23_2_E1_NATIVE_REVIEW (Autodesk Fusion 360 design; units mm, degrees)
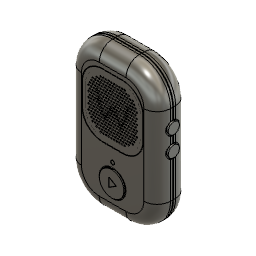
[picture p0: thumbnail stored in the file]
description: Open CASCADE Model
part number: 23_2_E1_FRONT_CONTROL_REVISION
description: Part Number
part number: 11_status_lightpipe_part
part number: 11_status_lightpipe
part number: 08_play_guide_part
part number: 08_play_guide
part number: 13_volume_down_diaphragm_part
part number: 13_volume_down_diaphragm
part number: 09_play_cap_part
part number: 09_play_cap
part number: 13_PTT_diaphragm_part
base_feature "Base Feature1"
base_feature "Base Feature1"
base_feature "Base Feature1"
base_feature "Base Feature1"
base_feature "Base Feature1"
base_feature "Base Feature1"
base_feature "Base Feature1"
base_feature "Base Feature1"
base_feature "Base Feature1"
base_feature "Base Feature1"
base_feature "Base Feature1"
base_feature "Base Feature1"
base_feature "Base Feature1"
base_feature "Base Feature1"
base_feature "Base Feature1"
base_feature "Base Feature1"
base_feature "Base Feature1"
base_feature "Base Feature1"
base_feature "Base Feature1"
base_feature "Base Feature1"
base_feature "Base Feature1"
base_feature "Base Feature1"
base_feature "Base Feature1"
base_feature "Base Feature1"
base_feature "Base Feature1"
base_feature "Base Feature1"
base_feature "Base Feature1"
base_feature "Base Feature1"
base_feature "Base Feature1"
base_feature "Base Feature1"
base_feature "Base Feature1"
base_feature "Base Feature1"
base_feature "Base Feature1"
base_feature "Base Feature1"
base_feature "Base Feature1"
base_feature "Base Feature1"
base_feature "Base Feature1"
base_feature "Base Feature1"
base_feature "Base Feature1"
base_feature "Base Feature1"
base_feature "Base Feature1"
base_feature "Base Feature1"
base_feature "Base Feature1"
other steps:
create_component "CreateComponent1"
create_component "CreateComponent1"
create_component "CreateComponent1"
create_component "CreateComponent2"
create_component "CreateComponent1"
create_component "CreateComponent3"
create_component "CreateComponent1"
create_component "CreateComponent4"
create_component "CreateComponent1"
create_component "CreateComponent5"
create_component "CreateComponent1"
create_component "CreateComponent6"
create_component "CreateComponent1"
create_component "CreateComponent7"
create_component "CreateComponent1"
create_component "CreateComponent8"
create_component "CreateComponent1"
create_component "CreateComponent9"
create_component "CreateComponent1"
create_component "CreateComponent10"
create_component "CreateComponent1"
create_component "CreateComponent11"
create_component "CreateComponent1"
create_component "CreateComponent12"
create_component "CreateComponent1"
create_component "CreateComponent13"
create_component "CreateComponent1"
create_component "CreateComponent14"
create_component "CreateComponent1"
create_component "CreateComponent15"
create_component "CreateComponent1"
create_component "CreateComponent16"
create_component "CreateComponent1"
create_component "CreateComponent17"
create_component "CreateComponent1"
create_component "CreateComponent18"
create_component "CreateComponent1"
create_component "CreateComponent19"
create_component "CreateComponent1"
create_component "CreateComponent20"
create_component "CreateComponent1"
create_component "CreateComponent21"
create_component "CreateComponent1"
create_component "CreateComponent22"
create_component "CreateComponent1"
create_component "CreateComponent23"
create_component "CreateComponent1"
create_component "CreateComponent24"
create_component "CreateComponent1"
create_component "CreateComponent25"
create_component "CreateComponent1"
create_component "CreateComponent26"
create_component "CreateComponent1"
create_component "CreateComponent27"
create_component "CreateComponent1"
create_component "CreateComponent28"
create_component "CreateComponent1"
create_component "CreateComponent29"
create_component "CreateComponent1"
create_component "CreateComponent30"
create_component "CreateComponent1"
create_component "CreateComponent31"
create_component "CreateComponent1"
create_component "CreateComponent32"
create_component "CreateComponent1"
create_component "CreateComponent33"
create_component "CreateComponent1"
create_component "CreateComponent34"
create_component "CreateComponent1"
create_component "CreateComponent35"
create_component "CreateComponent1"
create_component "CreateComponent36"
create_component "CreateComponent1"
create_component "CreateComponent37"
create_component "CreateComponent1"
create_component "CreateComponent38"
create_component "CreateComponent1"
create_component "CreateComponent39"
create_component "CreateComponent1"
create_component "CreateComponent40"
create_component "CreateComponent1"
create_component "CreateComponent41"
create_component "CreateComponent1"
create_component "CreateComponent42"
create_component "CreateComponent1"
create_component "CreateComponent43"
create_component "CreateComponent1"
